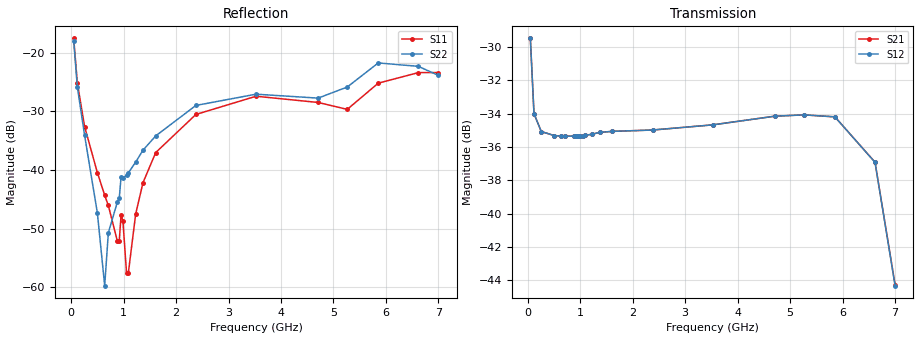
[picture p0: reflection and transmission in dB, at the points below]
! Integrated Device Technology
! Corporate Headquarters
! 6024 Silver Creek Valley Road
! San Jose, CA 95138  USA
! Phone:  1-408-284-8200
! Toll Free:  1-800-223-1366
! Webpage:  http://www.idt.com/
! Timing and RF Division
! 515 Groton Road, Suite 102
! Westford, MA 01886-6024
! Device:  F2258
! Description: Voltage Variable RF Attenuator
! Frequency:  50.0 -  6000.00 MHz
! Package:  3x3 mm Thin QFN Plastic Package: 16 pin
! Ports:  2 RF, 2 DC
!  Pin  1  = NC
!  Pin  2  = NC
!  Pin  3  = RF2  = Port 2
!  Pin  4  = GND
!  Pin  5  = Vdd
!  Pin  6  = NC
!  Pin  7  = VCTRL
!  Pin  8  = NC
!  Pin  9  = GND
!  Pin 10  = RF1  = Port 1
!  Pin 11  = NC
!  Pin 12  = NC
!  Pin 13  = NC
!  Pin 14  = NC
!  Pin 15  = NC
!  Pin 16  = NC
! Vcntrl:  2.190 Volts
! Vdd:  +3.300 Volts
! Current:  1.150 mA
! Data:  The device was measured on a the F2258 evaluation board which has
!  individual transmission lines to the RF pins.  Data was collected
!  using a calibrated network analyzer.  The evaluation board was
!  de-embedded using a TRL calibration technique.
!  The reference plane is the edge of the package pin.
! Misc:  SN 10
!  Action Tracker AT0285
! Date Measured:  2014-12-10
! Date:  2016-01-13  MJV
! Note:
!  Integrated Device Technology supplies this data as a sample of measured
!  data at the package pin for this product.  Your particular data for this
!  product may vary.
!  Data was taken at 25 degrees C.
!  Integrated Device Technology reserves the right to change this data at anytime.
!Freq_(GHz)  S11M_(dB)  S11P_(deg)  S21M_(dB)  S21P_(deg)  S12M_(dB)  S12P_(deg)  S22M_(dB)  S22P_(deg)
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# GHz S dB R 50
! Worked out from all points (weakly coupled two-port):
!   201 points, 50 MHz to 7 GHz, reference 50 ohm
!   highest |S21| = -29.49 dB at 50 MHz (marker M1); lowest = -44.3 dB at 7 GHz (marker M2)
!   lowest |S11| = -57.6 dB at 1.058 GHz (marker M3), VSWR 1.00, Z = 49.9 + j0.0547 ohm
!   |S11| at or under -10 dB: start of sweep to end of sweep
!   |S22| runs from -59.7 to -18.0 dB; largest |S21 - S12| = 7.2e-05
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0.05  -17.55 -111.0  -29.49 -68.2  -29.49 -68.2  -17.95 -110.8
0.1195  -25.12 -106.8  -34.01 -36.7  -34.01 -36.7  -25.83 -104.9
0.2585  -32.61 -111.8  -35.08 -18.7  -35.08 -18.7  -34.11 -107.2
0.50175  -40.46 -121.9  -35.32 -11.2  -35.32 -11.2  -47.36 -118.4
0.64075  -44.30 -127.8  -35.36 -9.7  -35.36 -9.7  -59.73 157.9
0.71025  -46.05 -137.2  -35.36 -9.2  -35.37 -9.2  -50.70 108.2
0.884  -52.18 166.5  -35.35 -8.5  -35.35 -8.5  -45.41 98.9
0.91875  -52.11 150.5  -35.35 -8.4  -35.35 -8.4  -44.78 97.5
0.9535  -47.60 -162.6  -35.36 -8.3  -35.36 -8.3  -41.14 111.2
0.98825  -48.72 -174.4  -35.34 -8.2  -35.34 -8.1  -41.44 108.4
1.05775  -57.64 155.3  -35.33 -8.0  -35.33 -8.0  -40.83 92.6
1.0925  -57.49 120.0  -35.31 -8.0  -35.31 -8.0  -40.47 88.9
1.2315  -47.51 46.5  -35.24 -8.0  -35.24 -8.0  -38.65 68.4
1.3705  -42.16 37.0  -35.13 -8.4  -35.13 -8.5  -36.62 58.1
1.61375  -37.02 32.7  -35.07 -9.7  -35.07 -9.7  -34.18 47.0
2.37825  -30.53 48.2  -34.99 -13.3  -34.99 -13.3  -28.99 39.9
3.525  -27.42 91.6  -34.68 -19.8  -34.68 -19.8  -27.07 65.0
4.7065  -28.48 95.6  -34.16 -29.0  -34.16 -28.9  -27.74 56.5
5.2625  -29.66 54.3  -34.08 -35.1  -34.08 -35.1  -25.85 19.0
5.85325  -25.19 29.8  -34.20 -45.7  -34.20 -45.7  -21.74 -3.9
6.61775  -23.39 49.7  -36.92 -68.7  -36.93 -68.7  -22.32 -45.5
7  -23.38 84.5  -44.27 -61.8  -44.33 -61.2  -23.87 -129.5
